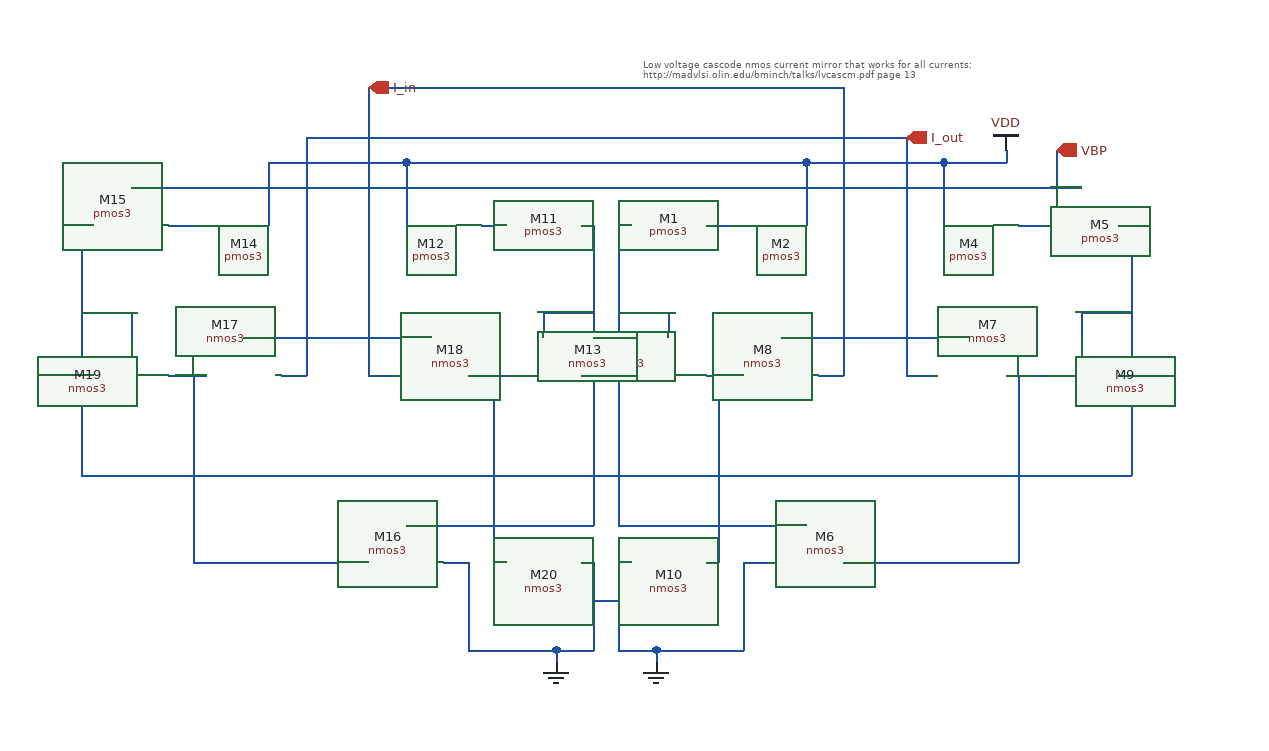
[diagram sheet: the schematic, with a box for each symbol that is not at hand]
v {xschem version=3.4.3 file_version=1.2
}
G {}
K {}
V {}
S {}
E {}
T {Low voltage cascode nmos current mirror that works for all currents: 
http://madvlsi.olin.edu/bminch/talks/lvcascm.pdf page 13} 270 -520 0 0 0.2 0.2 {}
N 320 -260 350 -260 {
lab=#net1}
N 510 -430 510 -380 {
lab=VDD}
N 250 -380 250 -260 {
lab=#net2}
N 250 -260 260 -260 {
lab=#net2}
N 250 -310 290 -310 {
lab=#net2}
N 290 -310 290 -290 {
lab=#net2}
N 250 -110 250 -40 {
lab=GND}
N 280 -40 280 -30 {
lab=GND}
N 620 -310 620 -290 {
lab=#net3}
N 620 -310 660 -310 {
lab=#net3}
N 650 -260 660 -260 {
lab=#net3}
N 660 -380 660 -260 {
lab=#net3}
N 370 -410 540 -410 {
lab=VBP}
N 400 -430 400 -380 {
lab=VDD}
N 560 -260 590 -260 {
lab=#net4}
N 380 -290 530 -290 {
lab=I_out}
N 410 -260 430 -260 {
lab=I_out}
N 430 -290 430 -260 {
lab=I_out}
N 480 -260 500 -260 {
lab=I_out}
N 280 -40 330 -40 {
lab=GND}
N 270 -140 360 -140 {
lab=#net2}
N 250 -140 270 -140 {
lab=#net2}
N 250 -260 250 -140 {
lab=#net2}
N 570 -260 570 -110 {
lab=#net4}
N 480 -450 480 -260 {
lab=I_out}
N 360 -140 400 -140 {
lab=#net2}
N 430 -110 570 -110 {
lab=#net4}
N 330 -260 330 -110 {
lab=#net1}
N 250 -40 280 -40 {
lab=GND}
N 290 -410 370 -410 {
lab=VBP}
N 320 -380 340 -380 {
lab=#net5}
N 250 -380 260 -380 {
lab=#net2}
N 570 -380 590 -380 {
lab=#net6}
N 540 -410 620 -410 {
lab=VBP}
N 650 -380 660 -380 {
lab=#net3}
N 320 -110 330 -110 {
lab=#net1}
N 250 -110 260 -110 {
lab=GND}
N 330 -40 350 -40 {
lab=GND}
N 350 -110 350 -40 {
lab=GND}
N 350 -110 370 -110 {
lab=GND}
N 130 -260 160 -260 {
lab=#net7}
N -30 -430 -30 -380 {
lab=VDD}
N 230 -380 230 -260 {
lab=#net2}
N 220 -260 230 -260 {
lab=#net2}
N 190 -310 230 -310 {
lab=#net2}
N 190 -310 190 -290 {
lab=#net2}
N 230 -110 230 -40 {
lab=GND}
N 200 -40 200 -30 {
lab=GND}
N -140 -310 -140 -290 {
lab=#net3}
N -180 -310 -140 -310 {
lab=#net3}
N -180 -260 -170 -260 {
lab=#net3}
N -180 -380 -180 -260 {
lab=#net3}
N -60 -410 110 -410 {
lab=VBP}
N 80 -430 80 -380 {
lab=VDD}
N -110 -260 -80 -260 {
lab=#net8}
N -50 -290 100 -290 {
lab=I_out}
N 50 -260 70 -260 {
lab=I_out}
N 50 -290 50 -260 {
lab=I_out}
N -20 -260 0 -260 {
lab=I_out}
N 150 -40 200 -40 {
lab=GND}
N 120 -140 210 -140 {
lab=#net2}
N 210 -140 230 -140 {
lab=#net2}
N 230 -260 230 -140 {
lab=#net2}
N -90 -260 -90 -110 {
lab=#net8}
N 0 -450 0 -260 {
lab=I_out}
N 80 -140 120 -140 {
lab=#net2}
N -90 -110 50 -110 {
lab=#net8}
N 150 -260 150 -110 {
lab=#net7}
N 200 -40 230 -40 {
lab=GND}
N 600 -440 600 -410 {
lab=VBP}
N 110 -410 190 -410 {
lab=VBP}
N 140 -380 160 -380 {
lab=#net9}
N 220 -380 230 -380 {
lab=#net2}
N -110 -380 -90 -380 {
lab=#net10}
N -140 -410 -60 -410 {
lab=VBP}
N -180 -380 -170 -380 {
lab=#net3}
N 150 -110 160 -110 {
lab=#net7}
N 220 -110 230 -110 {
lab=GND}
N 130 -40 150 -40 {
lab=GND}
N 130 -110 130 -40 {
lab=GND}
N 110 -110 130 -110 {
lab=GND}
N 230 -80 250 -80 {
lab=GND}
N 230 -290 250 -290 {
lab=#net2}
N 660 -260 660 -180 {
lab=#net3}
N -180 -180 660 -180 {
lab=#net3}
N -180 -260 -180 -180 {
lab=#net3}
N 190 -410 290 -410 {
lab=VBP}
N 50 -490 50 -480 {
lab=I_out}
N 50 -490 430 -490 {
lab=I_out}
N 430 -490 430 -480 {
lab=I_out}
N 400 -430 510 -430 {
lab=VDD}
N -30 -430 80 -430 {
lab=VDD}
N -0 -450 480 -450 {
lab=I_out}
N 510 -430 560 -430 {
lab=VDD}
N 560 -440 560 -430 {
lab=VDD}
N 80 -430 400 -430 {
lab=VDD}
N 50 -480 50 -290 {}
N 430 -480 430 -290 {}
C {madvlsi/pmos3.sym} 290 -380 3 1 {name=M1
L=4
W=32
body=VDD
nf=1
mult=1
ad="'int((nf+1)/2) * W/nf * 0.29'" 
pd="'2*int((nf+1)/2) * (W/nf + 0.29)'"
as="'int((nf+2)/2) * W/nf * 0.29'" 
ps="'2*int((nf+2)/2) * (W/nf + 0.29)'"
nrd="'0.29 / W'" nrs="'0.29 / W'"
sa=0 sb=0 sd=0
model=pfet_01v8
spiceprefix=X
}
C {madvlsi/pmos3.sym} 370 -380 1 0 {name=M2
L=4
W=32
body=VDD
nf=1
mult=1
ad="'int((nf+1)/2) * W/nf * 0.29'" 
pd="'2*int((nf+1)/2) * (W/nf + 0.29)'"
as="'int((nf+2)/2) * W/nf * 0.29'" 
ps="'2*int((nf+2)/2) * (W/nf + 0.29)'"
nrd="'0.29 / W'" nrs="'0.29 / W'"
sa=0 sb=0 sd=0
model=pfet_01v8
spiceprefix=X
}
C {madvlsi/nmos3.sym} 290 -260 3 1 {name=M3
L=4
W=32
body=GND
nf=1
mult=4
ad="'int((nf+1)/2) * W/nf * 0.29'" 
pd="'2*int((nf+1)/2) * (W/nf + 0.29)'"
as="'int((nf+2)/2) * W/nf * 0.29'" 
ps="'2*int((nf+2)/2) * (W/nf + 0.29)'"
nrd="'0.29 / W'" nrs="'0.29 / W'"
sa=0 sb=0 sd=0
model=nfet_01v8
spiceprefix=X
}
C {madvlsi/pmos3.sym} 540 -380 3 1 {name=M4
L=4
W=32
body=VDD
nf=1
mult=1
ad="'int((nf+1)/2) * W/nf * 0.29'" 
pd="'2*int((nf+1)/2) * (W/nf + 0.29)'"
as="'int((nf+2)/2) * W/nf * 0.29'" 
ps="'2*int((nf+2)/2) * (W/nf + 0.29)'"
nrd="'0.29 / W'" nrs="'0.29 / W'"
sa=0 sb=0 sd=0
model=pfet_01v8
spiceprefix=X
}
C {madvlsi/pmos3.sym} 620 -380 3 1 {name=M5
L=4
W=32
body=VDD
nf=1
mult=1
ad="'int((nf+1)/2) * W/nf * 0.29'" 
pd="'2*int((nf+1)/2) * (W/nf + 0.29)'"
as="'int((nf+2)/2) * W/nf * 0.29'" 
ps="'2*int((nf+2)/2) * (W/nf + 0.29)'"
nrd="'0.29 / W'" nrs="'0.29 / W'"
sa=0 sb=0 sd=0
model=pfet_01v8
spiceprefix=X
}
C {madvlsi/nmos3.sym} 400 -110 3 1 {name=M6
L=4
W=32
body=GND
nf=1
mult=4
ad="'int((nf+1)/2) * W/nf * 0.29'" 
pd="'2*int((nf+1)/2) * (W/nf + 0.29)'"
as="'int((nf+2)/2) * W/nf * 0.29'" 
ps="'2*int((nf+2)/2) * (W/nf + 0.29)'"
nrd="'0.29 / W'" nrs="'0.29 / W'"
sa=0 sb=0 sd=0
model=nfet_01v8
spiceprefix=X
}
C {madvlsi/nmos3.sym} 530 -260 1 0 {name=M7
L=4
W=32
body=GND
nf=1
mult=1
ad="'int((nf+1)/2) * W/nf * 0.29'" 
pd="'2*int((nf+1)/2) * (W/nf + 0.29)'"
as="'int((nf+2)/2) * W/nf * 0.29'" 
ps="'2*int((nf+2)/2) * (W/nf + 0.29)'"
nrd="'0.29 / W'" nrs="'0.29 / W'"
sa=0 sb=0 sd=0
model=nfet_01v8
spiceprefix=X
}
C {madvlsi/nmos3.sym} 380 -260 3 1 {name=M8
L=4
W=32
body=GND
nf=1
mult=1
ad="'int((nf+1)/2) * W/nf * 0.29'" 
pd="'2*int((nf+1)/2) * (W/nf + 0.29)'"
as="'int((nf+2)/2) * W/nf * 0.29'" 
ps="'2*int((nf+2)/2) * (W/nf + 0.29)'"
nrd="'0.29 / W'" nrs="'0.29 / W'"
sa=0 sb=0 sd=0
model=nfet_01v8
spiceprefix=X
}
C {madvlsi/nmos3.sym} 620 -260 1 0 {name=M9
L=4
W=32
body=GND
nf=1
mult=1
ad="'int((nf+1)/2) * W/nf * 0.29'" 
pd="'2*int((nf+1)/2) * (W/nf + 0.29)'"
as="'int((nf+2)/2) * W/nf * 0.29'" 
ps="'2*int((nf+2)/2) * (W/nf + 0.29)'"
nrd="'0.29 / W'" nrs="'0.29 / W'"
sa=0 sb=0 sd=0
model=nfet_01v8
spiceprefix=X
}
C {madvlsi/nmos3.sym} 290 -110 1 0 {name=M10
L=4
W=32
body=GND
nf=1
mult=1
ad="'int((nf+1)/2) * W/nf * 0.29'" 
pd="'2*int((nf+1)/2) * (W/nf + 0.29)'"
as="'int((nf+2)/2) * W/nf * 0.29'" 
ps="'2*int((nf+2)/2) * (W/nf + 0.29)'"
nrd="'0.29 / W'" nrs="'0.29 / W'"
sa=0 sb=0 sd=0
model=nfet_01v8
spiceprefix=X
}
C {madvlsi/gnd.sym} 280 -30 0 1 {name=l3 lab=GND}
C {madvlsi/vdd.sym} 560 -440 0 0 {name=l1 lab=VDD}
C {devices/opin.sym} 480 -450 0 0 {name=p3 lab=I_out}
C {madvlsi/pmos3.sym} 190 -380 1 0 {name=M11
L=4
W=32
body=VDD
nf=1
mult=1
ad="'int((nf+1)/2) * W/nf * 0.29'" 
pd="'2*int((nf+1)/2) * (W/nf + 0.29)'"
as="'int((nf+2)/2) * W/nf * 0.29'" 
ps="'2*int((nf+2)/2) * (W/nf + 0.29)'"
nrd="'0.29 / W'" nrs="'0.29 / W'"
sa=0 sb=0 sd=0
model=pfet_01v8
spiceprefix=X
}
C {madvlsi/pmos3.sym} 110 -380 3 1 {name=M12
L=4
W=32
body=VDD
nf=1
mult=1
ad="'int((nf+1)/2) * W/nf * 0.29'" 
pd="'2*int((nf+1)/2) * (W/nf + 0.29)'"
as="'int((nf+2)/2) * W/nf * 0.29'" 
ps="'2*int((nf+2)/2) * (W/nf + 0.29)'"
nrd="'0.29 / W'" nrs="'0.29 / W'"
sa=0 sb=0 sd=0
model=pfet_01v8
spiceprefix=X
}
C {madvlsi/nmos3.sym} 190 -260 1 0 {name=M13
L=4
W=32
body=GND
nf=1
mult=4
ad="'int((nf+1)/2) * W/nf * 0.29'" 
pd="'2*int((nf+1)/2) * (W/nf + 0.29)'"
as="'int((nf+2)/2) * W/nf * 0.29'" 
ps="'2*int((nf+2)/2) * (W/nf + 0.29)'"
nrd="'0.29 / W'" nrs="'0.29 / W'"
sa=0 sb=0 sd=0
model=nfet_01v8
spiceprefix=X
}
C {madvlsi/pmos3.sym} -60 -380 1 0 {name=M14
L=4
W=32
body=VDD
nf=1
mult=1
ad="'int((nf+1)/2) * W/nf * 0.29'" 
pd="'2*int((nf+1)/2) * (W/nf + 0.29)'"
as="'int((nf+2)/2) * W/nf * 0.29'" 
ps="'2*int((nf+2)/2) * (W/nf + 0.29)'"
nrd="'0.29 / W'" nrs="'0.29 / W'"
sa=0 sb=0 sd=0
model=pfet_01v8
spiceprefix=X
}
C {madvlsi/pmos3.sym} -140 -380 1 0 {name=M15
L=4
W=32
body=VDD
nf=1
mult=1
ad="'int((nf+1)/2) * W/nf * 0.29'" 
pd="'2*int((nf+1)/2) * (W/nf + 0.29)'"
as="'int((nf+2)/2) * W/nf * 0.29'" 
ps="'2*int((nf+2)/2) * (W/nf + 0.29)'"
nrd="'0.29 / W'" nrs="'0.29 / W'"
sa=0 sb=0 sd=0
model=pfet_01v8
spiceprefix=X
}
C {madvlsi/nmos3.sym} 80 -110 1 0 {name=M16
L=4
W=32
body=GND
nf=1
mult=4
ad="'int((nf+1)/2) * W/nf * 0.29'" 
pd="'2*int((nf+1)/2) * (W/nf + 0.29)'"
as="'int((nf+2)/2) * W/nf * 0.29'" 
ps="'2*int((nf+2)/2) * (W/nf + 0.29)'"
nrd="'0.29 / W'" nrs="'0.29 / W'"
sa=0 sb=0 sd=0
model=nfet_01v8
spiceprefix=X
}
C {madvlsi/nmos3.sym} -50 -260 3 1 {name=M17
L=4
W=32
body=GND
nf=1
mult=1
ad="'int((nf+1)/2) * W/nf * 0.29'" 
pd="'2*int((nf+1)/2) * (W/nf + 0.29)'"
as="'int((nf+2)/2) * W/nf * 0.29'" 
ps="'2*int((nf+2)/2) * (W/nf + 0.29)'"
nrd="'0.29 / W'" nrs="'0.29 / W'"
sa=0 sb=0 sd=0
model=nfet_01v8
spiceprefix=X
}
C {madvlsi/nmos3.sym} 100 -260 1 0 {name=M18
L=4
W=32
body=GND
nf=1
mult=1
ad="'int((nf+1)/2) * W/nf * 0.29'" 
pd="'2*int((nf+1)/2) * (W/nf + 0.29)'"
as="'int((nf+2)/2) * W/nf * 0.29'" 
ps="'2*int((nf+2)/2) * (W/nf + 0.29)'"
nrd="'0.29 / W'" nrs="'0.29 / W'"
sa=0 sb=0 sd=0
model=nfet_01v8
spiceprefix=X
}
C {madvlsi/nmos3.sym} -140 -260 3 1 {name=M19
L=4
W=32
body=GND
nf=1
mult=1
ad="'int((nf+1)/2) * W/nf * 0.29'" 
pd="'2*int((nf+1)/2) * (W/nf + 0.29)'"
as="'int((nf+2)/2) * W/nf * 0.29'" 
ps="'2*int((nf+2)/2) * (W/nf + 0.29)'"
nrd="'0.29 / W'" nrs="'0.29 / W'"
sa=0 sb=0 sd=0
model=nfet_01v8
spiceprefix=X
}
C {madvlsi/nmos3.sym} 190 -110 3 1 {name=M20
L=4
W=32
body=GND
nf=1
mult=1
ad="'int((nf+1)/2) * W/nf * 0.29'" 
pd="'2*int((nf+1)/2) * (W/nf + 0.29)'"
as="'int((nf+2)/2) * W/nf * 0.29'" 
ps="'2*int((nf+2)/2) * (W/nf + 0.29)'"
nrd="'0.29 / W'" nrs="'0.29 / W'"
sa=0 sb=0 sd=0
model=nfet_01v8
spiceprefix=X
}
C {madvlsi/gnd.sym} 200 -30 0 0 {name=l5 lab=GND}
C {devices/ipin.sym} 600 -440 0 1 {name=p4 lab=VBP
}
C {devices/ipin.sym} 50 -490 2 1 {name=p5 lab=I_in
}
